VERSION 5.8 ;
BUSBITCHARS "[]" ;

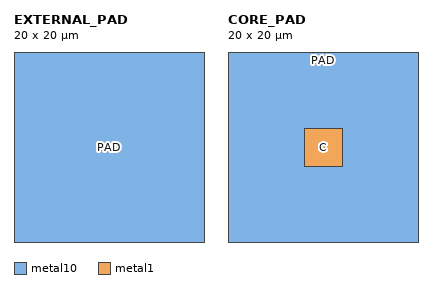
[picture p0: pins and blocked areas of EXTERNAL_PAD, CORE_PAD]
MACRO EXTERNAL_PAD
  CLASS PAD ;
  ORIGIN 0 0 ;
  SIZE 20 BY 20 ;
  SYMMETRY X Y R90 ;
  PIN PAD
    DIRECTION INOUT ;
    USE SIGNAL ;
    PORT
      LAYER metal10 ;
        RECT 0 0 20 20 ;
    END
  END PAD
END EXTERNAL_PAD

MACRO CORE_PAD
  CLASS PAD ;
  ORIGIN 0 0 ;
  SIZE 20 BY 20 ;
  SYMMETRY X Y R90 ;
  PIN PAD
    DIRECTION INOUT ;
    USE SIGNAL ;
    PORT
      LAYER metal10 ;
        RECT 0 0 20 20 ;
    END
  END PAD
  PIN C
    DIRECTION INPUT ;
    USE SIGNAL ;
    PORT
      LAYER metal1 ;
        RECT 8 8 12 12 ;
    END
  END C
END CORE_PAD

END LIBRARY
